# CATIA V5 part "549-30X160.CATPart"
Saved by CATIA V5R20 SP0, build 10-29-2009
Part number: 549-30X160
Definition: NONE
Nomenclature: 549-30X160
Source: Unknown
Description: 549-30X160
Bounding box of the stored display mesh (mm): x 0 to 160, y -17.5 to 17.5, z -17.5 to 17.5
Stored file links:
  C:\Users\Utente\Desktop\IO LAVORO\3D X SITO CF\X SITO\PLASTICA\549\549-30X160.CATPart

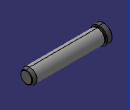
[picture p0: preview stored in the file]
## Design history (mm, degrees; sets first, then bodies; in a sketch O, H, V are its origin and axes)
Body1 "549-30X160" (main body)
  Solid1: solid without history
